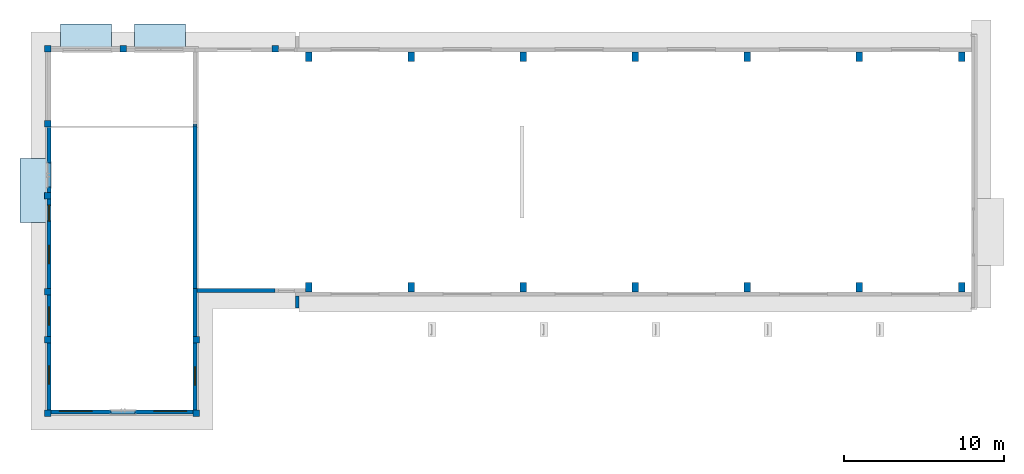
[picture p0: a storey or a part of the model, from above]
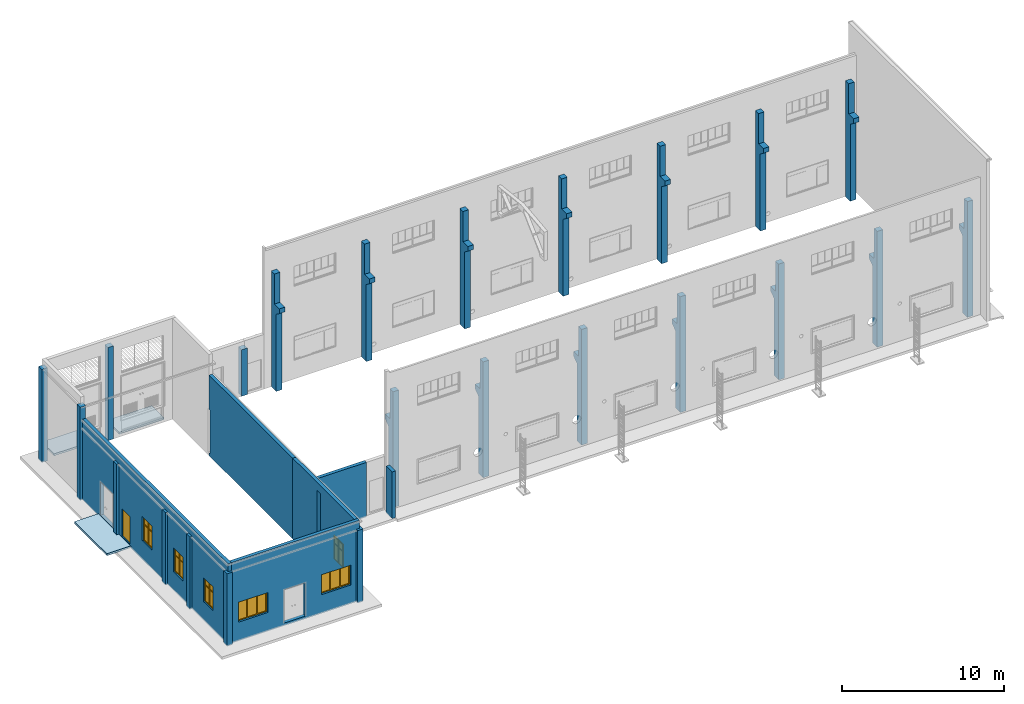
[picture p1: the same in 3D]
Properties of the parts of a building model (IFC2X3)

# File
Description: ViewDefinition [CoordinationView_V2.0]
File name: 项目编号
Time: 2023-02-14T13:37:09
Written by: The EXPRESS Data Manager Version 5.02.0100.07 : 28 Aug 2013
Made in: 20170223_1515(x64) - Exporter 18.0.0.420 - Alternate UI 18.0.0.420
Comment: STEP Physical File produced by: The EXPRESS Data Manager Version 5.02.0100.07 : 28 Aug 2013 * Module: EDMstepFileFactory/EDMstandAlone * Creation date: Tue Feb 14 13:37:09 2023 * Host: SD-20221111XOZW * Database: C:\Users\Administrator\AppData\Local\Temp\{36A0414B-4797-43F5-85F7-71999CD56A17}\ifc * Database version: 5507 * Database creation date: Tue Feb 14 13:37:07 2023 * Schema: IFC2X3 * Model: DataRepository.ifc * Model creation date: Tue Feb 14 13:37:07 2023 * Header model: DataRepository.ifc_HeaderModel * Header model creation date: Tue Feb 14 13:37:07 2023 * EDMuser: sdai-user * EDMgroup: sdai-group * License ID and type: 5605 : Permanent license. Expiry date: * EDMstepFileFactory options: 020000

# IfcProject, 项目编号
LongName: 项目名称; Phase: 项目状态

# IfcSite, 表面:1735058
RefLatitude: 42, 21, 29, 879999; RefLongitude: -71, -3, -37, -79999; RefElevation: 0 mm

# IfcBuilding
Pset_BuildingCommon - NumberOfStoreys: 8

# IfcBuildingStorey (8)
Name | LongName | Elevation (mm)
室外地坪 | 室外地坪 | -200
±0.000 | ±0.000 | 0
3.3000 | 3.3000 | 3300
5.250 | 5.250 | 5250
6.790 | 6.790 | 6790
8.500(标顶) | 8.500(标顶) | 8500
10.390 | 10.390 | 10390
13.170 | 13.170 | 13170

# IfcBeam: T型轨道:T型轨道 (2)
In: 3.3000
Type - PredefinedType: BEAM
Pset_BeamCommon - LoadBearing: yes; IsExternal: no; Reference: T型轨道; Slope: 0 deg
Name (T型轨道:T型轨道:...) | Span (mm)
1687506 | 41999
1687612 | 42120

# IfcBuildingElementProxy: 3mX7100 (6)
In: ±0.000
Type - Material: 砖石建筑 - 瓷砖
Pset_BuildingElementProxyCommon - Reference: 3mX7100
Name (基于墙的墙面装饰:3mX7100:...)
1731941
1732105
1732126
1732146
1732166
1732186

# IfcBuildingElementProxy: 3mX7360 (6)
In: ±0.000
Type - Material: 砖石建筑 - 瓷砖
Pset_BuildingElementProxyCommon - Reference: 3mX7360
Name (基于墙的墙面装饰:3mX7360:...)
1726696
1726797
1726826
1726846
1726866
1726886

# IfcBuildingElementProxy: T-1 (2)
In: ±0.000
Type - Material: 彩钢
Pset_BuildingElementProxyCommon - Reference: T-1
Name (变压器室钢梯:T-1:...)
1701790
1702238

# IfcBuildingElementProxy: 丁香 - 3.0 米 (6)
In: ±0.000
Pset_BuildingElementProxyCommon - Reference: 丁香 - 3.0 米
Name (RPC 灌木:丁香 - 3.0 米:...)
1743988
1744024
1744054
1744084
1747032
1747047

# IfcBuildingElementProxy: 墙饰条:压顶 (10)
Pset_BuildingElementProxyCommon - Reference: 压顶
Name (墙饰条:...) | In
5 x 压顶 | ±0.000
压顶 | 3.3000
4 x 压顶 | 室外地坪

# IfcBuildingElementProxy: 墙饰条:室外散水
In: 室外地坪
Pset_BuildingElementProxyCommon - Reference: 室外散水

# IfcBuildingElementProxy: 封檐板:屋面支撑 (6)
In: 8.500(标顶)
Pset_BuildingElementProxyCommon - Reference: 屋面支撑
Name (封檐板:...) | Group
屋面支撑 | 模型组:阵列组 1:1715373
屋面支撑 | 模型组:阵列组 1:1715384
屋面支撑 | 模型组:阵列组 1:1715414
屋面支撑 | 模型组:阵列组 2:1715539
屋面支撑 | 模型组:阵列组 2:1715550
屋面支撑 | 模型组:阵列组 2:1715584

# IfcBuildingElementProxy: 最上层房顶钢架 (3)
Type - Material: 钢材
Pset_BuildingElementProxyCommon - Reference: 最上层房顶钢架
Name (最上层房顶钢架:最上层房顶钢架:...) | In
1707689 | 室外地坪
1713818 | 3.3000
1713828 | 3.3000

# IfcBuildingElementProxy: 桥式吊车, 桥式吊车:桥式吊车:1699437
In: ±0.000
Type - Material: 吊车
Pset_BuildingElementProxyCommon - Reference: 桥式吊车

# IfcBuildingElementProxy: 直梯 (5)
In: 室外地坪
Type - Material: 彩钢
Pset_BuildingElementProxyCommon - Reference: 直梯
Name (直梯:直梯:...) | Group
1731006 | 模型组:室外平台:1731657
1731743 | 模型组:室外平台:1731772
1731796 | 模型组:室外平台:1731824
1731850 | 模型组:室外平台:1731878
1731904 | 模型组:室外平台:1731932

# IfcBuildingElementProxy: 直梯 2, 直梯:直梯 2:1735262
In: 3.3000
Type - Material: 彩钢
Pset_BuildingElementProxyCommon - Reference: 直梯 2

# IfcBuildingElementProxy: 直梯 3, 直梯:直梯 3:1739555
In: ±0.000
Type - Material: 彩钢
Pset_BuildingElementProxyCommon - Reference: 直梯 3

# IfcBuildingElementProxy: 直爬梯 (2)
Type - Material: 彩钢
Pset_BuildingElementProxyCommon - Reference: 直爬梯
Name (直爬梯:直爬梯:...) | In
1729337 | 3.3000
1739052 | 8.500(标顶)

# IfcBuildingElementProxy: 穿屋面雨水斗 (3)
In: ±0.000
Pset_BuildingElementProxyCommon - Reference: 穿屋面雨水斗
Name (穿屋面雨水斗:穿屋面雨水斗:...)
1734337
1734631
1734649

# IfcBuildingElementProxy: 穿屋面雨水斗 (3)
In: ±0.000
Type - Material: 金属 - 钢, 抛光
Pset_BuildingElementProxyCommon - Reference: 穿屋面雨水斗
Name (穿屋面雨水斗:穿屋面雨水斗:...)
1734385
1734743
1734765

# IfcBuildingElementProxy: 类型 1 (3)
Pset_BuildingElementProxyCommon - Reference: 类型 1
Name (穿墙雨水斗:类型 1:...) | In
1703334 | 3.3000
1704988 | 3.3000
1734840 | ±0.000

# IfcBuildingElementProxy: 类型 1 (3)
Type - Material: 金属 - 钢, 抛光
Pset_BuildingElementProxyCommon - Reference: 类型 1
Name (穿墙雨水斗:类型 1:...) | In
1702901 | ±0.000
1704784 | 6.790
1734772 | ±0.000

# IfcBuildingElementProxy: 钢架 (7)
Type - Material: 钢架
Pset_BuildingElementProxyCommon - Reference: 钢架
Name (钢架:钢架:...) | In
1689282 | 8.500(标顶)
1689591 | ±0.000
1689599 | ±0.000
1689609 | ±0.000
1689619 | ±0.000
1689627 | ±0.000
1689637 | ±0.000

# IfcColumn: 400 x 400mm (20)
Type - ElementType: 400 x 400mm; PredefinedType: COLUMN; Material: 混凝土 - 结构柱涂黑
Pset_ColumnCommon - Reference: 400 x 400mm; LoadBearing: yes; IsExternal: no
Name (M_矩形-结构柱:400 x 400mm:...) | In
1672086 | 室外地坪
1672087 | 室外地坪
1672088 | 室外地坪
1672089 | 室外地坪
1672091 | 室外地坪
1672092 | 室外地坪
1672222 | 室外地坪
1672223 | 室外地坪
1672224 | ±0.000
1672225 | ±0.000
1672226 | ±0.000
1672227 | ±0.000
1672228 | ±0.000
1672246 | 室外地坪
1672301 | ±0.000
1672398 | ±0.000
1672481 | ±0.000
1672482 | ±0.000
1672484 | ±0.000
1672485 | 室外地坪

# IfcColumn: 400 x 600mm (2)
In: ±0.000
Type - ElementType: 400 x 600mm; PredefinedType: COLUMN; Material: 混凝土 - 结构柱涂黑
Pset_ColumnCommon - LoadBearing: yes; IsExternal: no; Reference: 400 x 600mm
Name (M_矩形-结构柱:400 x 600mm:...)
1672501
1673044

# IfcColumn: W250X73 (5)
In: ±0.000
Type - ElementType: W250X73; PredefinedType: COLUMN; Material: 金属 - 钢 - 345 MPa
Pset_ColumnCommon - LoadBearing: yes; IsExternal: no; Reference: W250X73
Name (W-宽翼缘-柱:W250X73:...) | Group
1748951 | 模型组:室外平台:1731657
1749257 | 模型组:室外平台:1731772
1749260 | 模型组:室外平台:1731824
1749263 | 模型组:室外平台:1731878
1749266 | 模型组:室外平台:1731932

# IfcColumn: 牛腿柱 (14)
In: 室外地坪
Type - ElementType: 牛腿柱; PredefinedType: COLUMN; Material: 混凝土 - 结构柱涂黑
Pset_ColumnCommon - LoadBearing: yes; IsExternal: no; Reference: 牛腿柱
Name (牛腿柱:牛腿柱:...)
1672583
1672744
1672881
1672891
1672940
1672950
1672992
1672993
1673003
1673004
1673014
1673015
1673025
1673026

# IfcDoor: M-1 (2)
In: ±0.000
Type - ParameterTakesPrecedence: no; Sizeable: no; Material: 门 - 嵌板, 抛光不锈钢, 门 - 框架
OverallHeight: 3300 mm; OverallWidth: 3000 mm
Pset_DoorCommon - IsExternal: no; Reference: M-1
Name (双扇平开门M-1:M-1:...)
1690993
1690994

# IfcDoor: M-4 (2)
In: ±0.000
Type - ParameterTakesPrecedence: no; Sizeable: no; Material: 抛光不锈钢, 门 - 框架, 门 - 嵌板
OverallHeight: 2500 mm; OverallWidth: 1500 mm
Pset_DoorCommon - IsExternal: no; Reference: M-4
Name (双扇开平门M-4:M-4:...)
1716379
1722664

# IfcDoor: M3, 单开门:M3:1699987
In: ±0.000
Type - OperationType: SINGLE_SWING_RIGHT; ParameterTakesPrecedence: no; Sizeable: no; Material: 塑钢, 木质 - 木材
Type - 单开门:M3:1699987 - PanelOperation: SWINGING
OverallHeight: 2400 mm; OverallWidth: 1000 mm
Pset_DoorCommon - IsExternal: no; Reference: M3

# IfcDoor: M5, 单开门:M5:1699798
In: ±0.000
Type - OperationType: SINGLE_SWING_LEFT; ParameterTakesPrecedence: no; Sizeable: no; Material: 塑钢, 木质 - 木材
Type - 单开门:M5:1699798 - PanelOperation: SWINGING
OverallHeight: 2100 mm; OverallWidth: 1000 mm
Pset_DoorCommon - IsExternal: no; Reference: M5

# IfcDoor: M5, 单开门:M5:1723732
In: ±0.000
Type - OperationType: SINGLE_SWING_LEFT; ParameterTakesPrecedence: no; Sizeable: no; Material: 塑钢, 木质 - 木材
Type - 单开门:M5:1723732 - PanelOperation: SWINGING
OverallHeight: 2100 mm; OverallWidth: 1000 mm
Pset_DoorCommon - IsExternal: no; Reference: M5

# IfcDoor: M5 (3)
In: ±0.000
Type - OperationType: SINGLE_SWING_RIGHT; ParameterTakesPrecedence: no; Sizeable: no; Material: 塑钢, 木质 - 木材
Type - 单开门:M5:1684655 - PanelOperation: SWINGING
OverallHeight: 2100 mm; OverallWidth: 1000 mm
Pset_DoorCommon - IsExternal: no; Reference: M5
Name (单开门:M5:...)
1684655
1684738
1686355

# IfcDoor: M5, 单开门:M5:1722521
In: ±0.000
Type - OperationType: SINGLE_SWING_RIGHT; ParameterTakesPrecedence: no; Sizeable: no; Material: 塑钢, 木质 - 木材
Type - 单开门:M5:1722521 - PanelOperation: SWINGING
OverallHeight: 2100 mm; OverallWidth: 1000 mm
Pset_DoorCommon - IsExternal: no; Reference: M5

# IfcDoor: M7, 单开门:M7:1686404
In: ±0.000
Type - OperationType: SINGLE_SWING_RIGHT; ParameterTakesPrecedence: no; Sizeable: no; Material: 塑钢, 木质 - 木材
Type - 单开门:M7:1686404 - PanelOperation: SWINGING
OverallHeight: 2100 mm; OverallWidth: 700 mm
Pset_DoorCommon - IsExternal: no; Reference: M7

# IfcDoor: 门M2, 门M2:门M2:1684301
In: ±0.000
Type - OperationType: DOUBLE_DOOR_SINGLE_SWING; ParameterTakesPrecedence: no; Sizeable: no
Type - 门M2:门M2:1684301 - PanelOperation: SWINGING
OverallHeight: 3300 mm; OverallWidth: 3000 mm
Pset_DoorCommon - IsExternal: no; Reference: 门M2

# IfcFlowSegment: 檐沟:檐槽:19886, 檐沟:檐槽:1715200
In: 8.500(标顶)
Type - ElementType: 檐沟:檐槽:19886; PredefinedType: GUTTER
Pset_DistributionFlowElementCommon - Reference: 檐槽

# IfcFlowSegment: 檐沟:通风楼:1708186 (2)
In: 13.170
Type - ElementType: 檐沟:通风楼:1708186; PredefinedType: GUTTER
Pset_DistributionFlowElementCommon - Reference: 通风楼
Name (檐沟:通风楼:...)
1708381
1708390

# IfcOpeningElement: Opening (70)
Name | In
单开门:M5:1723732:1 | ±0.000
基本墙:砖墙240mm:1675823:1 | 室外地坪
基本墙:内砖墙240mm:1676898:1 | ±0.000
5 x 基本墙:外砖墙240:1699860 | 室外地坪
房顶窗(c-8):房顶窗(c-8):1712290:1 | 10.390
楼板:室外雨篷:1727594:2 | ±0.000 | Group: 模型组:室外平台:1731657
楼板:室外雨篷:1731730:2 | ±0.000 | Group: 模型组:室外平台:1731772
楼板:室外雨篷:1731784:2 | ±0.000 | Group: 模型组:室外平台:1731824
楼板:室外雨篷:1731838:2 | ±0.000 | Group: 模型组:室外平台:1731878
楼板:室外雨篷:1731892:2 | ±0.000 | Group: 模型组:室外平台:1731932
房顶窗(c-8):房顶窗(c-8):1712472:1 | 10.390
房顶窗(c-8):房顶窗(c-8):1712514:1 | 10.390
单开门:M5:1722521:1 | 室外地坪
双扇开平门M-4:M-4:1722664:1 | 室外地坪
推拉窗(c-2):推拉窗(c-2):1722759:1 | 室外地坪
推拉窗(c-2):推拉窗(c-2):1723686:1 | 室外地坪
推拉窗(c-2):推拉窗(c-2):1723724:1 | 室外地坪
双扇平开门M-1:M-1:1690994:1 | 室外地坪
双扇平开门M-1:M-1:1690993:1 | 室外地坪
推拉窗（c-5）:推拉窗（c-5）:1690995:1 | 室外地坪
推拉窗（c-5）:推拉窗（c-5）:1690996:1 | 室外地坪
百页窗（c-6）:铝合金百页:1702742:1 | 室外地坪
百页窗（c-6）:铝合金百页:1702783:1 | 室外地坪
单开门:M5:1684655:1 | ±0.000
单开门:M5:1684738:1 | ±0.000
单开门:M5:1686355:1 | ±0.000
单开门:M7:1686404:1 | ±0.000
推拉窗（c-9）:推拉窗（c-9）:1684797:1 | ±0.000
推拉窗（c-9）:推拉窗（c-9）:1686335:1 | ±0.000
平开窗（c-3）:平开窗（c-3）:1716377:1 | 室外地坪
平开窗（c-3）:平开窗（c-3）:1716378:1 | 室外地坪
双扇开平门M-4:M-4:1716379:1 | 室外地坪
推拉窗(c-2):推拉窗(c-2):1741473:1 | 室外地坪
单开门:M5:1699798:1 | 室外地坪
推拉窗(c-1):C-1:1681308:1 | 室外地坪
推拉窗(c-1):C-1:1681388:1 | 室外地坪
推拉窗(c-1):C-1:1681410:1 | 室外地坪
推拉窗(c-1):C-1:1681422:1 | 室外地坪
推拉窗(c-1):C-1:1681434:1 | 室外地坪
推拉窗(c-1):C-1:1681446:1 | 室外地坪
推拉窗(c-1):C-1:1681629:1 | 室外地坪
推拉窗(c-1):C-1:1681790:1 | 室外地坪
推拉窗(c-1):C-1:1681802:1 | 室外地坪
推拉窗(c-1):C-1:1681814:1 | 室外地坪
推拉窗(c-1):C-1:1681826:1 | 室外地坪
推拉窗(c-1):C-1:1681838:1 | 室外地坪
推拉窗(c-7):推拉窗(c-7):1682767:1 | 室外地坪
推拉窗(c-7):推拉窗(c-7):1682943:1 | 室外地坪
推拉窗(c-7):推拉窗(c-7):1682965:1 | 室外地坪
推拉窗(c-7):推拉窗(c-7):1682986:1 | 室外地坪
推拉窗(c-7):推拉窗(c-7):1683007:1 | 室外地坪
推拉窗(c-7):推拉窗(c-7):1683028:1 | 室外地坪
推拉窗(c-7):推拉窗(c-7):1683045:1 | 室外地坪
推拉窗(c-7):推拉窗(c-7):1683171:1 | 室外地坪
推拉窗(c-7):推拉窗(c-7):1683192:1 | 室外地坪
推拉窗(c-7):推拉窗(c-7):1683213:1 | 室外地坪
推拉窗(c-7):推拉窗(c-7):1683234:1 | 室外地坪
推拉窗(c-7):推拉窗(c-7):1683255:1 | 室外地坪
门M2:门M2:1684301:1 | 室外地坪
平开窗（c-3）:平开窗（c-3）:1740845:1 | 室外地坪
单开门:M3:1699987:1 | 室外地坪
房顶窗(c-8):房顶窗(c-8):1720588:1 | 10.390
房顶窗(c-8):房顶窗(c-8):1720607:1 | 10.390
房顶窗(c-8):房顶窗(c-8):1720372:1 | 10.390
房顶窗(c-8):房顶窗(c-8):1720628:1 | 10.390
房顶窗(c-8):房顶窗(c-8):1712555:1 | 10.390

# IfcRailing: 栏杆扶手:900mm 圆管 (14)
Pset_RailingCommon - IsExternal: no; Reference: 900mm 圆管; Height: 1219.2 mm
Name (栏杆扶手:900mm 圆管:...) | In | Group
1727779 | 3.3000 | 模型组:室外平台:1731657
1731482 | 3.3000 | 模型组:室外平台:1731657
1731738 | 3.3000 | 模型组:室外平台:1731772
1731765 | 3.3000 | 模型组:室外平台:1731772
1731792 | 3.3000 | 模型组:室外平台:1731824
1731818 | 3.3000 | 模型组:室外平台:1731824
1731846 | 3.3000 | 模型组:室外平台:1731878
1731872 | 3.3000 | 模型组:室外平台:1731878
1731900 | 3.3000 | 模型组:室外平台:1731932
1731926 | 3.3000 | 模型组:室外平台:1731932
1735692 | 8.500(标顶)
1735890 | 8.500(标顶)
1740014 | 6.790
1740116 | 6.790

# IfcRamp: 坡道:坡道 1:350, 坡道:坡道 1:1684356
In: 室外地坪
Pset_RampCommon - IsExternal: no; Reference: 坡道 1

# IfcRampFlight: 坡道:坡道 1:350, 坡道:坡道 1:1684356:1
In: 室外地坪
Material: 混凝土 - 现场浇筑
Pset_RampFlightCommon - Reference: 坡道 1

# IfcRoof: 基本屋顶:常规 - 125mm (3)
Pset_RoofCommon - IsExternal: yes; Reference: 常规 - 125mm
Name (基本屋顶:常规 - 125mm:...) | In | TotalArea (m2) | ProjectedArea (m2)
1703050 | 3.3000 | 90.8903 | 90.872
1704474 | 5.250 | 157.741 | 157.709
1722483 | 6.790 | 38.8944 | 38.8944

# IfcRoof: 基本屋顶:常规 - 125mm:1602348 (2)
Material: 彩钢-蓝
Pset_RoofCommon - IsExternal: yes; Reference: 常规 - 125mm
Name (基本屋顶:常规 - 125mm:...) | In | TotalArea (m2) | ProjectedArea (m2)
1705492 | 10.390 | 499.354 | 490.262
1706025 | 13.170 | 159.142 | 158.144

# IfcSlab: 基本屋顶:常规 - 125mm (5)
PredefinedType: ROOF; Material: 彩钢-蓝 125 mm
Pset_SlabCommon - IsExternal: yes; Reference: 常规 - 125mm
Name (基本屋顶:常规 - 125mm:...) | In | PitchAngle (deg)
2 x 1703050 | 3.3000 | 1.15
2 x 1704474 | 5.250 | 1.15
1722483 | 6.790 | 0

# IfcSlab: 楼板:C 150 - 平台 30+120 (6)
PredefinedType: FLOOR; Material: C_保温-聚苯 30 mm, C_混凝土 - 轻集料混凝土 - 密集 120 mm
Pset_SlabCommon - IsExternal: no; LoadBearing: no; PitchAngle: 0 deg; Reference: C 150 - 平台 30+120
Name (楼板:C 150 - 平台 30+120:...) | In
1724097 | 室外地坪
1724163 | 室外地坪
1724175 | 室外地坪
1724269 | ±0.000
1727285 | ±0.000
1739182 | 3.3000

# IfcSlab: 楼板:室外雨篷 (14)
PredefinedType: FLOOR; Material: C_砼-沙/水泥找平 20 mm, C_混凝土 - 钢筋混凝土 - 密集 80 mm
Pset_SlabCommon - IsExternal: no; LoadBearing: no; Reference: 室外雨篷
Name (楼板:室外雨篷:...) | In | PitchAngle (deg)
1723783 | ±0.000 | 0
1723890 | ±0.000 | 0
1723911 | 3.3000 | 0
1723978 | 3.3000 | 0
1724018 | 3.3000 | 0
1724311 | ±0.000 | 0
1727376 | ±0.000 | 0
1727594 | ±0.000 | Group: 模型组:室外平台:1731657
1731730 | ±0.000 | Group: 模型组:室外平台:1731772
1731784 | ±0.000 | Group: 模型组:室外平台:1731824
1731838 | ±0.000 | Group: 模型组:室外平台:1731878
1731892 | ±0.000 | Group: 模型组:室外平台:1731932
1735031 | ±0.000 | 0
1735100 | ±0.000 | 0

# IfcSlab: 楼板:常规 240 - 50+70+120 (4)
In: ±0.000
PredefinedType: FLOOR; Material: C_砼-沙/水泥找平 50 mm, C_砼-加气砌块 70 mm, C_混凝土 - 钢筋混凝土 - 密集 120 mm
Pset_SlabCommon - IsExternal: no; LoadBearing: no; Reference: 常规 240 - 50+70+120; PitchAngle: 0 deg
Name (楼板:常规 240 - 50+70+120:...)
1676946
1676972
1676992
1684422

# IfcWall: 基本墙:外砖墙240, 基本墙:外砖墙240:1675982
In: 室外地坪
Type - PredefinedType: STANDARD; Material: 砖石建筑 - 砖 240 mm
Pset_WallCommon - Reference: 外砖墙240; LoadBearing: no; IsExternal: yes; ExtendToStructure: yes

# IfcWallStandardCase: 基本墙:内砖墙240mm (9)
In: ±0.000
Type - PredefinedType: STANDARD; Material: 砖石建筑 - 砖 240 mm
Pset_WallCommon - LoadBearing: no; ExtendToStructure: no; IsExternal: yes; Reference: 内砖墙240mm
Name (基本墙:内砖墙240mm:...)
1675210
1675364
1676486
1676512
1676795
1676852
1676898
1721855
1721892

# IfcWallStandardCase: 基本墙:外砖墙240 (6)
In: 室外地坪
Type - PredefinedType: STANDARD; Material: 砖石建筑 - 砖 240 mm
Pset_WallCommon - Reference: 外砖墙240; LoadBearing: no; IsExternal: yes
Name (基本墙:外砖墙240:...) | ExtendToStructure
1675045 | no
1675122 | no
1675531 | no
1675576 | no
1699860 | yes
1721417 | no

# IfcWallStandardCase: 基本墙:沟壁150 (3)
In: ±0.000
Type - PredefinedType: STANDARD; Material: C_砼- 水泥焦渣 150 mm
Pset_WallCommon - LoadBearing: no; ExtendToStructure: no; IsExternal: yes; Reference: 沟壁150
Name (基本墙:沟壁150:...)
1677131
1677188
1677212

# IfcWallStandardCase: 基本墙:砖墙240mm (14)
Type - PredefinedType: STANDARD; Material: 砖石建筑 - 砖 240 mm
Pset_WallCommon - LoadBearing: no; IsExternal: yes; Reference: 砖墙240mm
Name (基本墙:砖墙240mm:...) | In | ExtendToStructure
1675653 | 室外地坪 | no
1675823 | 室外地坪 | no
1676086 | 室外地坪 | no
1676297 | 3.3000 | no
1698404 | 室外地坪 | no
1698499 | 室外地坪 | no
1699961 | 室外地坪 | no
1705158 | 10.390 | no
1705222 | 10.390 | no
1705360 | 10.390 | yes
1705441 | 10.390 | yes
1720874 | 室外地坪 | no
1720940 | 室外地坪 | no
1721645 | 室外地坪 | no

# IfcWindow: C-1 (12)
In: ±0.000
Type - ParameterTakesPrecedence: no; Sizeable: no; Material: 窗框, 玻璃, 窗套
OverallHeight: 1800 mm; OverallWidth: 3000 mm
Pset_WindowCommon - IsExternal: yes; Reference: C-1
Name (推拉窗(c-1):C-1:...)
1681308
1681388
1681410
1681422
1681434
1681446
1681629
1681790
1681802
1681814
1681826
1681838

# IfcWindow: 平开窗（c-3） (3)
In: ±0.000
Type - ParameterTakesPrecedence: no; Sizeable: no; Material: 窗框材质量, 玻璃, 金属－铝
OverallHeight: 1500 mm; OverallWidth: 2100 mm
Pset_WindowCommon - IsExternal: yes; Reference: 平开窗（c-3）
Name (平开窗（c-3）:平开窗（c-3）:...)
1716377
1716378
1740845

# IfcWindow: 房顶窗(c-8) (8)
In: 10.390
Type - ParameterTakesPrecedence: no; Sizeable: no; Material: 窗框, 玻璃
OverallHeight: 1200 mm; OverallWidth: 6940 mm
Pset_WindowCommon - IsExternal: yes; Reference: 房顶窗(c-8)
Name (房顶窗(c-8):房顶窗(c-8):...)
1712290
1712472
1712514
1712555
1720372
1720588
1720607
1720628

# IfcWindow: 推拉窗(c-2) (4)
In: ±0.000
Type - ParameterTakesPrecedence: no; Sizeable: no; Material: 玻璃, 窗框材质
OverallHeight: 1800 mm; OverallWidth: 1200 mm
Pset_WindowCommon - IsExternal: yes; Reference: 推拉窗(c-2)
Name (推拉窗(c-2):推拉窗(c-2):...)
1722759
1723686
1723724
1741473

# IfcWindow: 推拉窗(c-7) (12)
Type - ParameterTakesPrecedence: no; Sizeable: no; Material: 窗框材质, 玻璃
OverallHeight: 1500 mm; OverallWidth: 3000 mm
Pset_WindowCommon - IsExternal: yes; Reference: 推拉窗(c-7)
Name (推拉窗(c-7):推拉窗(c-7):...) | In
1682767 | ±0.000
1682943 | ±0.000
1682965 | ±0.000
1682986 | ±0.000
1683007 | ±0.000
1683028 | ±0.000
1683045 | ±0.000
1683171 | 3.3000
1683192 | 3.3000
1683213 | 3.3000
1683234 | 3.3000
1683255 | 3.3000

# IfcWindow: 推拉窗（c-5） (2)
In: ±0.000
Type - ParameterTakesPrecedence: no; Sizeable: no; Material: 窗框, 玻璃 2
OverallHeight: 900 mm; OverallWidth: 3000 mm
Pset_WindowCommon - IsExternal: yes; Reference: 推拉窗（c-5）
Name (推拉窗（c-5）:推拉窗（c-5）:...)
1690995
1690996

# IfcWindow: 推拉窗（c-9） (2)
In: ±0.000
Type - ParameterTakesPrecedence: no; Sizeable: no; Material: 玻璃, 金属－铝, 木质 - 木材
OverallHeight: 1800 mm; OverallWidth: 1500 mm
Pset_WindowCommon - IsExternal: yes; Reference: 推拉窗（c-9）
Name (推拉窗（c-9）:推拉窗（c-9）:...)
1684797
1686335

# IfcWindow: 铝合金百页 (2)
In: ±0.000
Type - ParameterTakesPrecedence: no; Sizeable: no; Material: 金属-铝
OverallHeight: 1800 mm; OverallWidth: 3000 mm
Pset_WindowCommon - IsExternal: yes; Reference: 铝合金百页
Name (百页窗（c-6）:铝合金百页:...)
1702742
1702783
